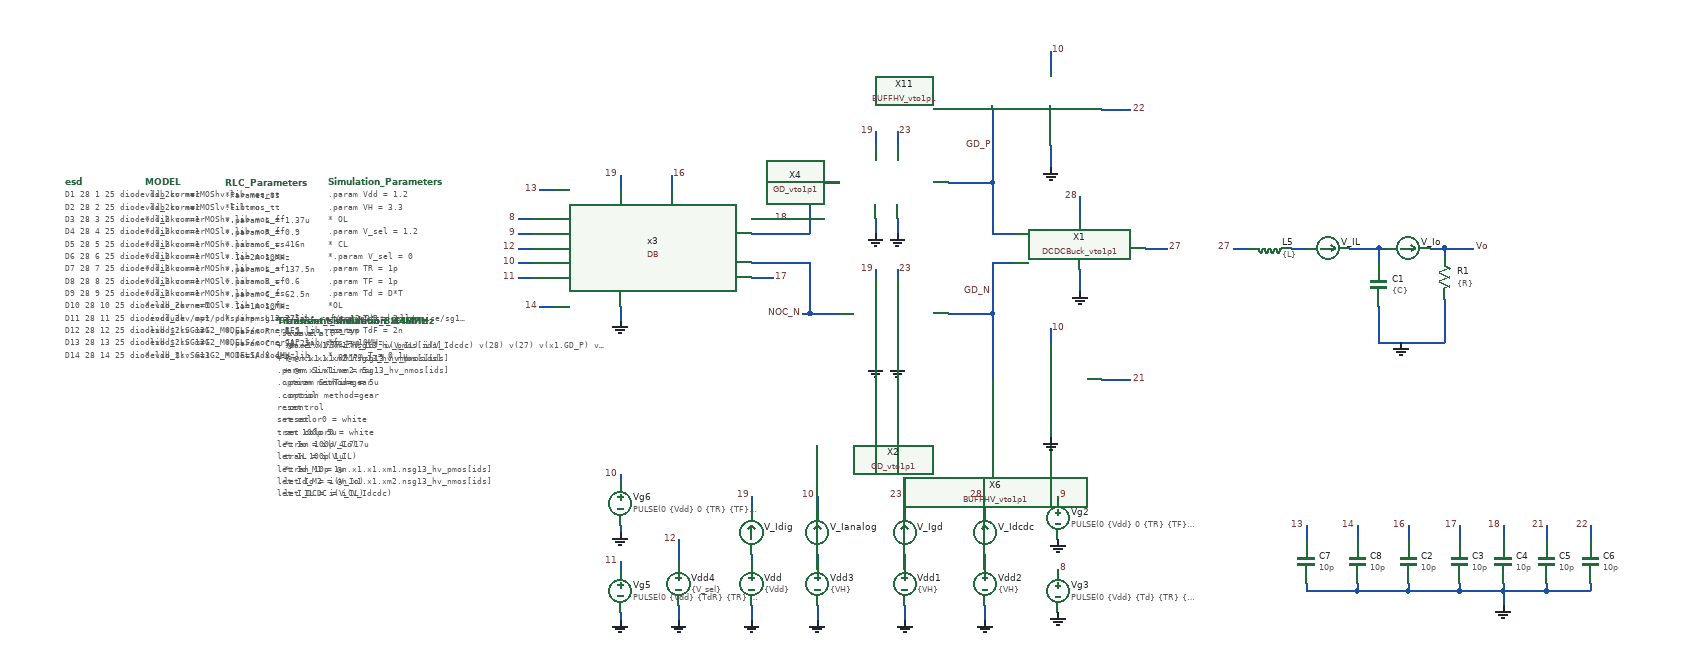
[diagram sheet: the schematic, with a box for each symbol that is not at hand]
v {xschem version=3.4.5 file_version=1.2
}
G {}
K {}
V {}
S {}
E {}
N -30 -230 -30 -210 {
lab=19}
N 150 -150 230 -150 {
lab=NOC_P}
N 150 -110 230 -110 {
lab=NOC_N}
N -140 -210 -120 -210 {
lab=13}
N -140 -50 -120 -50 {
lab=14}
N 420 -220 480 -220 {
lab=GD_P}
N 420 -40 480 -40 {
lab=GD_N}
N 480 -150 510 -150 {
lab=GD_P}
N 480 -220 480 -150 {
lab=GD_P}
N 480 -110 510 -110 {
lab=GD_N}
N 480 -110 480 -40 {
lab=GD_N}
N 600 -200 600 -170 {
lab=28}
N 690 -130 720 -130 {
lab=27}
N 600 -100 600 -70 {
lab=GND}
N 230 -110 230 -40 {
lab=NOC_N}
N 230 -220 230 -150 {
lab=NOC_P}
N 230 -220 270 -220 {
lab=NOC_P}
N 350 -100 350 -90 {
lab=23}
N 350 10 350 30 {
lab=GND}
N 350 -170 350 -150 {
lab=GND}
N 320 -100 320 -90 {
lab=19}
N 320 -290 320 -270 {
lab=19}
N 350 -290 350 -270 {
lab=23}
N 320 10 320 30 {
lab=GND}
N -30 -50 -30 -30 {
lab=GND}
N 320 -170 320 -150 {
lab=GND}
N 150 -90 180 -90 {
lab=17}
N 150 -170 180 -170 {
lab=18}
N 630 -320 670 -320 {
lab=22}
N 630 50 670 50 {
lab=21}
N 480 -320 480 -220 {
lab=GD_P}
N 480 -40 480 50 {
lab=GD_N}
N 560 -400 560 -370 {
lab=10}
N 560 -20 560 0 {
lab=10}
N 560 -270 560 -240 {
lab=GND}
N 560 100 560 130 {
lab=GND}
N 40 -230 40 -210 {
lab=16}
N -170 -170 -150 -170 {
lab=8}
N -170 -150 -150 -150 {
lab=9}
N 230 -40 270 -40 {
lab=NOC_N}
N 220 -220 230 -220 {
lab=NOC_P}
N 220 -40 230 -40 {
lab=NOC_N}
N -170 -130 -150 -130 {
lab=12}
N -170 -110 -150 -110 {
lab=10}
N -170 -90 -150 -90 {
lab=11}
N 150 360 150 380 {
lab=GND}
N 360 360 360 380 {
lab=GND}
N 360 290 360 310 {
lab=#net1}
N 360 210 360 230 {
lab=23}
N 150 210 150 230 {
lab=19}
N 150 290 150 300 {
lab=#net2}
N 470 360 470 380 {
lab=GND}
N 470 290 470 310 {
lab=#net3}
N 470 210 470 230 {
lab=28}
N 240 360 240 380 {
lab=GND}
N 240 290 240 310 {
lab=#net4}
N 240 210 240 230 {
lab=10}
N 50 360 50 380 {
lab=GND}
N 50 270 50 300 {
lab=12}
N -30 180 -30 190 {
lab=10}
N -30 250 -30 260 {
lab=GND}
N -30 300 -30 310 {
lab=11}
N -30 370 -30 380 {
lab=GND}
N 1050 330 1050 340 {
lab=GND}
N 1240 340 1300 340 {
lab=GND}
N 1300 330 1300 340 {
lab=GND}
N 1240 330 1240 340 {
lab=GND}
N 1180 340 1240 340 {
lab=GND}
N 1180 330 1180 340 {
lab=GND}
N 1120 340 1180 340 {
lab=GND}
N 1120 330 1120 340 {
lab=GND}
N 1050 340 1120 340 {
lab=GND}
N 1180 340 1180 360 {
lab=GND}
N 1050 250 1050 270 {
lab=16}
N 1120 250 1120 270 {
lab=17}
N 1180 250 1180 270 {
lab=18}
N 1240 250 1240 270 {
lab=21}
N 1300 250 1300 270 {
lab=22}
N 910 330 910 340 {
lab=GND}
N 980 330 980 340 {
lab=GND}
N 910 340 980 340 {
lab=GND}
N 910 250 910 270 {
lab=13}
N 980 250 980 270 {
lab=14}
N 980 340 1050 340 {
lab=GND}
N 1010 -130 1020 -130 {
lab=#net5}
N 1100 -130 1140 -130 {
lab=Vo}
N 1100 -60 1100 0 {
lab=GND}
N 1100 -130 1100 -120 {
lab=Vo}
N 1080 -130 1100 -130 {
lab=Vo}
N 1010 -130 1010 -110 {
lab=#net5}
N 970 -130 1010 -130 {
lab=#net5}
N 810 -130 830 -130 {
lab=27}
N 1010 0 1100 0 {
lab=GND}
N 1010 -50 1010 0 {
lab=GND}
N 890 -130 910 -130 {
lab=#net6}
C {lab_pin.sym} -30 -230 2 1 {name=p3 sig_type=std_logic lab=19}
C {lab_pin.sym} -140 -50 0 0 {name=p39 sig_type=std_logic lab=14}
C {lab_pin.sym} 670 -320 0 1 {name=p2 sig_type=std_logic lab=22}
C {lab_pin.sym} 670 50 0 1 {name=p4 sig_type=std_logic lab=21}
C {lab_pin.sym} 350 -290 2 0 {name=p6 sig_type=std_logic lab=23}
C {lab_pin.sym} 350 -100 2 0 {name=p7 sig_type=std_logic lab=23
}
C {lab_pin.sym} 600 -200 0 0 {name=p36 sig_type=std_logic lab=28}
C {lab_pin.sym} 720 -130 2 0 {name=p41 sig_type=std_logic lab=27}
C {lab_pin.sym} 320 -100 0 0 {name=p44 sig_type=std_logic lab=19}
C {lab_pin.sym} 320 -290 0 0 {name=p45 sig_type=std_logic lab=19}
C {lab_pin.sym} 180 -170 0 1 {name=p46 sig_type=std_logic lab=18
}
C {lab_pin.sym} 180 -90 0 1 {name=p47 sig_type=std_logic lab=17
}
C {code.sym} -790 -220 0 0 {name=esd only_toplevel=false spice_ignore=true value="
D1 28 1 25 diodevdd_2kv m=1
D2 28 2 25 diodevdd_2kv m=1
D3 28 3 25 diodevdd_2kv m=1
D4 28 4 25 diodevdd_2kv m=1
D5 28 5 25 diodevdd_2kv m=1
D6 28 6 25 diodevdd_2kv m=1
D7 28 7 25 diodevdd_2kv m=1
D8 28 8 25 diodevdd_2kv m=1
D9 28 9 25 diodevdd_2kv m=1
D10 28 10 25 diodevdd_2kv m=1
D11 28 11 25 diodevdd_2kv m=1
D12 28 12 25 diodevdd_2kv m=1
D13 28 13 25 diodevdd_2kv m=1
D14 28 14 25 diodevdd_2kv m=1
D15 28 15 25 diodevdd_2kv m=1
D16 28 16 25 diodevdd_2kv m=1
D17 28 17 25 diodevdd_2kv m=1
D18 28 18 25 diodevdd_2kv m=1
D19 28 19 25 diodevdd_2kv m=1
D20 28 20 25 diodevdd_2kv m=1
D21 28 21 25 diodevdd_2kv m=1
D22 28 22 25 diodevdd_2kv m=1
D23 28 23 25 diodevdd_2kv m=1
D24 28 24 25 diodevdd_2kv m=1
D25 28 25 25 diodevdd_2kv m=1
D26 28 26 25 diodevdd_2kv m=1
D27 28 27 25 diodevdd_2kv m=1
D28 28 28 25 diodevdd_2kv m=1

D29 28 1 25 diodevss_2kv m=1
D30 28 2 25 diodevss_2kv m=1
D31 28 3 25 diodevss_2kv m=1
D32 28 4 25 diodevss_2kv m=1
D33 28 5 25 diodevss_2kv m=1
D34 28 6 25 diodevss_2kv m=1
D35 28 7 25 diodevss_2kv m=1
D36 28 8 25 diodevss_2kv m=1
D37 28 9 25 diodevss_2kv m=1
D38 28 10 25 diodevss_2kv m=1
D39 28 11 25 diodevss_2kv m=1
D40 28 12 25 diodevss_2kv m=1
D41 28 13 25 diodevss_2kv m=1
D42 28 14 25 diodevss_2kv m=1
D43 28 15 25 diodevss_2kv m=1
D44 28 16 25 diodevss_2kv m=1
D45 28 17 25 diodevss_2kv m=1
D46 28 18 25 diodevss_2kv m=1
D47 28 19 25 diodevss_2kv m=1
D48 28 20 25 diodevss_2kv m=1
D49 28 21 25 diodevss_2kv m=1
D50 28 22 25 diodevss_2kv m=1
D51 28 23 25 diodevss_2kv m=1
D52 28 24 25 diodevss_2kv m=1
D53 28 25 25 diodevss_2kv m=1
D54 28 26 25 diodevss_2kv m=1
D55 28 27 25 diodevss_2kv m=1
D56 28 28 25 diodevss_2kv m=1
"}
C {lab_pin.sym} 40 -230 0 1 {name=p53 sig_type=std_logic lab=16
}
C {lab_pin.sym} 560 -400 2 0 {name=p59 sig_type=std_logic lab=10}
C {lab_pin.sym} 560 -20 2 0 {name=p60 sig_type=std_logic lab=10}
C {lab_pin.sym} 480 -270 2 1 {name=p63 sig_type=std_logic lab=GD_P}
C {lab_pin.sym} 480 -70 2 1 {name=p64 sig_type=std_logic lab=GD_N}
C {../BUFFHV/BUFFHV_vto1p1.sym} 510 -280 0 0 {name=X11}
C {../DCDCBuck/DCDCBuck_vto1p1.sym} 610 -110 0 0 {name=X1}
C {../BUFFHV/BUFFHV_vto1p1.sym} 510 90 0 0 {name=X6}
C {lab_pin.sym} -170 -170 0 0 {name=p48 sig_type=std_logic lab=8}
C {lab_pin.sym} -170 -150 0 0 {name=p49 sig_type=std_logic lab=9}
C {lab_pin.sym} 220 -220 2 1 {name=p50 sig_type=std_logic lab=NOC_P}
C {lab_pin.sym} 220 -40 2 1 {name=p51 sig_type=std_logic lab=NOC_N}
C {lab_pin.sym} -140 -210 0 0 {name=p52 sig_type=std_logic lab=13}
C {lab_pin.sym} -170 -130 0 0 {name=p55 sig_type=std_logic lab=12}
C {lab_pin.sym} -170 -110 0 0 {name=p56 sig_type=std_logic lab=10}
C {lab_pin.sym} -170 -90 0 0 {name=p58 sig_type=std_logic lab=11}
C {code.sym} -680 -220 0 0 {name=MODEL only_toplevel=true
format="tcleval( @value )"
value="

.lib cornerMOShv.lib mos_tt
.lib cornerMOSlv.lib mos_tt
*.lib cornerMOShv.lib mos_ff
*.lib cornerMOSlv.lib mos_ff
*.lib cornerMOShv.lib mos_ss
*.lib cornerMOSlv.lib mos_ss
*.lib cornerMOShv.lib mos_sf
*.lib cornerMOSlv.lib mos_sf
*.lib cornerMOShv.lib mos_fs
*.lib cornerMOSlv.lib mos_fs

.include /opt/pdks/ihp-sg13g2/libs.ref/sg13g2_stdcell/spice/sg13g2_stdcell.spice
.lib $::SG13G2_MODELS/cornerRES.lib res_typ
.lib $::SG13G2_MODELS/cornerCAP.lib cap_typ
*.lib $::SG13G2_MODELS/diodes.lib
"}
C {code.sym} -571 -219 0 0 {name=RLC_Parameters only_toplevel=false 
value="
*Parametros
*Filtro
*.param L = 1.37u
*.param R = 0.9
*.param C = 416n

* Io=2A 10MHz
*.param L = 137.5n
*.param R = 0.6
*.param C = 62.5n

* Io=1A 10MHz
*.param L = 275n
*.param R = 1.2
*.param C = 31.25n

* Io=1A 8.4MHz
.param L = 327n
.param R = 1.2
.param C = 37n

"}
C {devices/code.sym} -490 -30 0 1 {name=Transient_simulation_8.48MHz only_toplevel=false spice_ignore =false

value="
*.save all
.save v(Vo) i(V_Io) i(V_IL) i(V_Idcdc) v(28) v(27) v(x1.GD_P) v(22) v(x1.GD_N) v(21) v(x1.NOC_P) v(x1.NOC_N) v(17) v(18) v(x1.x10.PD_OUT) v(16) v(13) v(8) v(14) v(9) v(28) v(23) v(10) v(19)
+ @n.x1.x1.xm1.nsg13_hv_pmos[ids]
+ @n.x1.x1.xm2.nsg13_hv_nmos[ids]
.param SimTime = 5u

.option method=gear

.control
reset
set color0 = white
*tran 100p 4.717u 
tran 100p 1u
*tran 10p 1u
let Io = i(V_Io)
let IL = i(V_IL)
let Id_M1 = @n.x1.x1.xm1.nsg13_hv_pmos[ids]
let Id_M2 = @n.x1.x1.xm2.nsg13_hv_nmos[ids]
let I_DCDC = i(V_Idcdc)


let Vsd_M1 = v(28) - v(27)
let Vds_M2 = v(27)
let Vg_M1 = v(x1.GD_P)
let GD_P = v(22)
let Vg_M2 = v(x1.GD_N)
let GD_N = v(21)
let Vs_M1 = v(x1.NOC_P)
let NOC_P_BUFF = v(18)
let Vs_M2 = v(x1.NOC_N)
let NOC_N_BUFF = v(17)
let PD_OUT = v(x1.x10.PD_OUT)
let PD_BUFF = v(16)
let VINS_BUFF = v(13)
let VINS = v(8)
let VINR_BUFF = v(14)
let VINR = v(9) 

let Pin_DCDC = I_DCDC*v(28)
let P_GD_VH = v(23)*i(V_Igd)
let P_Analog = v(10)*i(V_Ianalog)
let P_DB = v(19)*i(V_Idig)
let P_M1 = Vsd_M1*Id_M1
let P_M2 = -Vds_M2*Id_M2


let Po = Io*v(Vo)

let DataMeasBegin = SimTime-1u

meas tran P_DB_mean AVG P_DB from=2.358u to=4.717u 
meas tran P_GD_mean AVG P_GD_VH from=2.358u to=4.717u
meas tran P_Analog_mean AVG P_Analog from=2.358u to=4.717u
meas tran Pin_DCDC_mean AVG Pin_DCDC from=2.358u to=4.717u

let Pin_tot_mean = P_DB_mean + P_GD_mean + Pin_DCDC_mean + P_Analog_mean
print Pin_tot_mean

meas tran Vo_mean AVG v(Vo) from=2.358u to=4.717u
meas tran Io_mean AVG Io from=2.358u to=4.717u
meas tran Po_mean AVG Po from=2.358u to=4.717u

meas tran P_M1_mean AVG P_M1 from=2.358u to=4.717u
meas tran P_M2_mean AVG P_M2 from=2.358u to=4.717u

meas TRAN tdR TRIG Vg_M1 VAL=0.33 RISE=1 TARG Vg_M2 VAL=0.33 RISE=1
meas TRAN tdF TRIG Vg_M1 VAL=2.97 FALL=1 TARG Vg_M2 VAL=2.97 FALL=1

let eff = 100*Po_mean/Pin_tot_mean
let eff_DCDC = 100*Po_mean/Pin_DCDC_mean
let loss_M1 = 100*P_M1_mean/Pin_tot_mean
let loss_M2 = 100*P_M2_mean/Pin_tot_mean
let loss_GD = 100*P_GD_mean/Pin_tot_mean
let loss_DB = 100*P_DB_mean/Pin_tot_mean
let loss_AB = 100*P_Analog_mean/Pin_tot_mean
let sumaPot = eff+loss_M1+loss_M2+loss_GD+loss_DB + loss_AB
print eff eff_DCDC loss_M1 loss_M2 loss_GD loss_DB loss_AB sumaPot 

plot Io IL
plot Id_M1 Id_M2
plot v(Vo)
plot Po 
*plot P_M1 P_M2
plot Vds_M2
plot Vg_M1 Vg_M2
*plot Vs_M1 Vs_M2
plot PD_OUT PD_BUFF
plot NOC_P_BUFF Vs_M1
plot NOC_N_BUFF Vs_M2
plot GD_P Vg_M1
plot GD_N Vg_M2
plot VINS VINS_BUFF
plot VINR VINR_BUFF

.endc



.end
"}
C {devices/code.sym} -500 -30 0 0 {name=Transient_simulation_8.44MHz only_toplevel=false spice_ignore =true

value="
.save all
+ @n.x1.x1.xm1.nsg13_hv_pmos[ids]
+ @n.x1.x1.xm2.nsg13_hv_nmos[ids]
.param SimTime = 5u

.option method=gear

.control
reset
set color0 = white
tran 100p 5u
let Io = i(V_Io)
let IL = i(V_IL)
let Id_M1 = @n.x1.x1.xm1.nsg13_hv_pmos[ids]
let Id_M2 = @n.x1.x1.xm2.nsg13_hv_nmos[ids]
let I_DCDC = i(V_Idcdc)

let Vsd_M1 = v(28) - v(27)
let Vds_M2 = v(27)
let Vg_M1 = v(22)
let Vg_M2 = v(21)
let Vs_M1 = v(18)
let Vs_M2 = v(17)

let Pin_DCDC = I_DCDC*v(28)
let P_GD_VH = v(23)*i(V_Igd)
let P_DB = v(19)*i(V_Idig)
let P_M1 = Vsd_M1*Id_M1
let P_M2 = -Vds_M2*Id_M2


let Po = Io*v(Vo)

let DataMeasBegin = SimTime-1u

meas tran P_DB_mean AVG P_DB from=2.3697u to=4.7393u 
meas tran P_GD_mean AVG P_GD_VH from=2.3697u to=4.7393u 
meas tran Pin_DCDC_mean AVG Pin_DCDC from=2.3697u to=4.7393u 

let Pin_tot_mean = P_DB_mean + P_GD_mean + Pin_DCDC_mean
print Pin_tot_mean

meas tran Vo_mean AVG v(Vo) from=2.3697u to=4.7393u 
meas tran Io_mean AVG Io from=2.3697u to=4.7393u 
meas tran Po_mean AVG Po from=2.3697u to=4.7393u 

meas tran P_M1_mean AVG P_M1 from=2.3697u to=4.7393u 
meas tran P_M2_mean AVG P_M2 from=2.3697u to=4.7393u 

meas TRAN tdR TRIG Vg_M1 VAL=0.33 RISE=1 TARG Vg_M2 VAL=0.33 RISE=1
meas TRAN tdF TRIG Vg_M1 VAL=2.97 FALL=1 TARG Vg_M2 VAL=2.97 FALL=1

let eff = 100*Po_mean/Pin_tot_mean
let eff_DCDC = 100*Po_mean/Pin_DCDC_mean
let loss_M1 = 100*P_M1_mean/Pin_tot_mean
let loss_M2 = 100*P_M2_mean/Pin_tot_mean
let loss_GD = 100*P_GD_mean/Pin_tot_mean
let loss_DB = 100*P_DB_mean/Pin_tot_mean
let sumaPot = eff+loss_M1+loss_M2+loss_GD+loss_DB
print eff eff_DCDC loss_M1 loss_M2 loss_GD loss_DB sumaPot

plot Io IL
plot Id_M1 Id_M2
plot v(Vo)
plot Po 
*plot P_M1 P_M2
plot Vds_M2
plot Vg_M1 Vg_M2
plot Vs_M1 Vs_M2

.endc



.end
"}
C {code.sym} -430 -220 0 0 {name=Simulation_Parameters only_toplevel=false 

value="
.param Vdd = 1.2
.param VH = 3.3

* OL
.param V_sel = 1.2
* CL
*.param V_sel = 0

.param TR = 1p
.param TF = 1p
.param Td = D*T

*OL
.param TdR = 2n
.param TdF = 2n

*fs = 10MHz
*.param T = 0.1u
*fs = 8.48MHz a Vo=1.2V
.param T = 0.11792u 
.param D = 0.615
*fs = 8.44MHz a Vo=1.8V
*.param T = 0.11848u 
*.param D = 0.4545

.option temp = 27
*.option KLU
*.option itl4=100
*.option method=gear
*.option maxord=2
*.option trtol=25
*.option lvltim=1
*.option tnum=1e9
*.option reltol=1e-3
*.option abstol=1e-10
*.option vntol=1e-4
*.option gmin=1e-10
*.option cshunt=1e-13

"}
C {vsource.sym} -30 340 0 1 {name=Vg5 value="PULSE(0 \{Vdd\} \{TdR\} \{TR\} \{TF\} \{T*D-TdR-TdF\} \{T\} 0)" savecurrent=false}
C {lab_pin.sym} -30 180 0 0 {name=p38 sig_type=std_logic lab=10}
C {gnd.sym} -30 260 0 1 {name=l17 lab=GND}
C {vsource.sym} -30 220 0 1 {name=Vg6 value="PULSE(0 \{Vdd\} 0 \{TR\} \{TF\} \{T*D\} \{T\} 0)" savecurrent=false}
C {lab_pin.sym} -30 300 0 0 {name=p54 sig_type=std_logic lab=11}
C {gnd.sym} -30 380 0 1 {name=l18 lab=GND}
C {vsource.sym} 150 330 0 0 {name=Vdd value=\{Vdd\} savecurrent=false}
C {lab_pin.sym} 150 210 0 0 {name=p57 sig_type=std_logic lab=19}
C {gnd.sym} 150 380 0 0 {name=l2 lab=GND}
C {vsource.sym} 360 330 0 0 {name=Vdd1 value=\{VH\} savecurrent=false}
C {lab_pin.sym} 360 210 0 0 {name=p65 sig_type=std_logic lab=23}
C {gnd.sym} 360 380 0 0 {name=l7 lab=GND}
C {ammeter.sym} 360 260 2 1 {name=V_Igd savecurrent=true spice_ignore=0}
C {ammeter.sym} 150 260 2 1 {name=V_Idig savecurrent=true spice_ignore=0}
C {devices/lab_pin.sym} 570 210 0 1 {name=p66 sig_type=std_logic lab=9
}
C {vsource.sym} 570 240 0 0 {name=Vg2 value="PULSE(0 \{Vdd\} 0 \{TR\} \{TF\} \{T*D\} \{T\} 0)" savecurrent=false}
C {devices/lab_pin.sym} 570 310 0 1 {name=p67 sig_type=std_logic lab=8}
C {vsource.sym} 570 340 0 0 {name=Vg3 value="PULSE(0 \{Vdd\} \{Td\} \{TR\} \{TF\} \{T*D\} \{T\} 0)" savecurrent=false}
C {gnd.sym} 570 270 0 1 {name=l4 lab=GND}
C {gnd.sym} 570 370 0 1 {name=l9 lab=GND}
C {vsource.sym} 470 330 0 0 {name=Vdd2 value=\{VH\} savecurrent=false}
C {lab_pin.sym} 470 210 0 0 {name=p68 sig_type=std_logic lab=28}
C {gnd.sym} 470 380 0 0 {name=l1 lab=GND}
C {ammeter.sym} 470 260 2 1 {name=V_Idcdc savecurrent=true spice_ignore=0}
C {vsource.sym} 240 330 0 0 {name=Vdd3 value=\{VH\} savecurrent=false}
C {lab_pin.sym} 240 210 0 0 {name=p69 sig_type=std_logic lab=10}
C {gnd.sym} 240 380 0 0 {name=l3 lab=GND}
C {ammeter.sym} 240 260 2 1 {name=V_Ianalog savecurrent=true spice_ignore=0}
C {vsource.sym} 50 330 0 0 {name=Vdd4 value=\{V_sel\} savecurrent=false}
C {lab_pin.sym} 50 270 0 0 {name=p70 sig_type=std_logic lab=12}
C {gnd.sym} 50 380 0 0 {name=l14 lab=GND}
C {capa.sym} 1050 300 0 0 {name=C2
m=1
value= 10p
footprint=1206
device="ceramic capacitor"}
C {capa.sym} 1120 300 0 0 {name=C3
m=1
value= 10p
footprint=1206
device="ceramic capacitor"}
C {capa.sym} 1180 300 0 0 {name=C4
m=1
value= 10p
footprint=1206
device="ceramic capacitor"}
C {capa.sym} 1240 300 0 0 {name=C5
m=1
value= 10p
footprint=1206
device="ceramic capacitor"}
C {capa.sym} 1300 300 0 0 {name=C6
m=1
value= 10p
footprint=1206
device="ceramic capacitor"}
C {gnd.sym} 1180 360 0 1 {name=l13 lab=GND}
C {lab_pin.sym} 1050 250 0 0 {name=p71 sig_type=std_logic lab=16
}
C {lab_pin.sym} 1120 250 0 0 {name=p72 sig_type=std_logic lab=17
}
C {lab_pin.sym} 1180 250 0 0 {name=p73 sig_type=std_logic lab=18
}
C {lab_pin.sym} 1240 250 0 0 {name=p74 sig_type=std_logic lab=21
}
C {lab_pin.sym} 1300 250 0 0 {name=p75 sig_type=std_logic lab=22
}
C {capa.sym} 910 300 0 0 {name=C7
m=1
value= 10p
footprint=1206
device="ceramic capacitor"}
C {capa.sym} 980 300 0 0 {name=C8
m=1
value= 10p
footprint=1206
device="ceramic capacitor"}
C {lab_pin.sym} 910 250 0 0 {name=p76 sig_type=std_logic lab=13
}
C {lab_pin.sym} 980 250 0 0 {name=p77 sig_type=std_logic lab=14
}
C {devices/lab_pin.sym} 810 -130 0 0 {name=p78 sig_type=std_logic lab=27
}
C {ind.sym} 860 -130 3 1 {name=L5
m=1
value= \{L\}
footprint=1206
device=inductor}
C {capa.sym} 1010 -80 0 0 {name=C1
m=1
value= \{C\}
footprint=1206
device="ceramic capacitor"}
C {ammeter.sym} 1050 -130 3 0 {name=V_Io savecurrent=true spice_ignore=0}
C {res.sym} 1100 -90 0 0 {name=R1
value= \{R\}
footprint=1206
device=resistor
m=1}
C {gnd.sym} 1040 0 0 0 {name=l6 lab=GND}
C {lab_pin.sym} 1140 -130 0 1 {name=p79 sig_type=std_logic lab=Vo}
C {ammeter.sym} 940 -130 3 0 {name=V_IL savecurrent=true spice_ignore=0}
C {gnd.sym} 600 -70 0 1 {name=l8 lab=GND}
C {/home/designer/shared/simulations/TORepo_IHPNov2024_TDBuck/design_data/xschem/Digital_Block/DB.sym} 0 -130 0 0 {name=x3}
C {gnd.sym} 320 -150 0 1 {name=l10 lab=GND}
C {gnd.sym} 350 -150 0 0 {name=l11 lab=GND}
C {gnd.sym} 350 30 0 0 {name=l12 lab=GND}
C {gnd.sym} 320 30 0 1 {name=l15 lab=GND}
C {gnd.sym} 560 -240 0 0 {name=l16 lab=GND}
C {gnd.sym} 560 130 0 0 {name=l19 lab=GND}
C {gnd.sym} -30 -30 0 0 {name=l20 lab=GND}
C {/home/designer/shared/simulations/IHP-sg13g2/Simulaciones/IHP_Tapeout24/GD/GD_vto1p1.sym} 300 0 0 0 {name=X2}
C {/home/designer/shared/simulations/IHP-sg13g2/Simulaciones/IHP_Tapeout24/GD/GD_vto1p1.sym} 300 -180 0 0 {name=X4}
